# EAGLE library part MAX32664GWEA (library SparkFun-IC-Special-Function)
Maxim MAX32664 Biometric Sensor Hub he MAX32664 is a sensor hub family with embedded firmware and algorithms for wearables. It seamlessly enables customer-desired sensor functionality, including communication with Maxim’s optical sensor solutions and delivering raw or calculated data to the outside world. This is achieved while keeping overall system power consumption in check. The MAX32664 Version A supports the MAX30101/ MAX30102 high-sensitivity pulse oximeter and heart rate sensor for wearable health for finger-based applications.

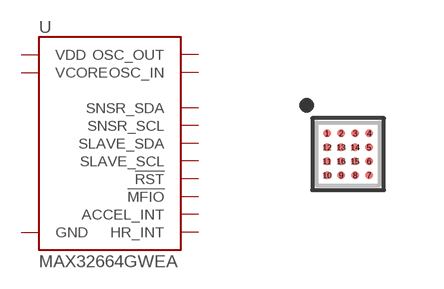
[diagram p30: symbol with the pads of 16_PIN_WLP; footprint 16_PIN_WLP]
Designator prefix U

## MAX32664GWEA (PROD_ID: IC-14271)  [16_PIN_WLP]
1  OSC_OUT
2  OSC_IN
3  VDD  pwr
4  VCORE  pwr
5  SNSR_SCL
6  HR_INT
9  SLAVE_SDA
10  SLAVE_SCL
12  !RST
13  GND  pwr
14  SNSR_SDA
15  ACCEL_INT
16  !MFIO

## Footprint 16_PIN_WLP (pad centres in mm)
16 Pin WLP Mechanical Specifications: Pad Size: .2mm Diameter Pin count: 16 Pin pitch: .35mm Package Size: 1.544mm x 1.572mm x .64mm Datasheet referenced for footprint
smd 0.2 x 0.2: 1 -0.532,0.518; 2 -0.182,0.518; 3 0.168,0.518; 4 0.518,0.518; 5 0.518,0.168; 6 0.518,-0.182; 7 0.518,-0.532; 8 0.168,-0.532; 9 -0.182,-0.532; 10 -0.532,-0.532; 11 -0.532,-0.182; 12 -0.532,0.168; 13 -0.182,0.168; 14 0.168,0.168; 15 0.168,-0.182; 16 -0.182,-0.182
